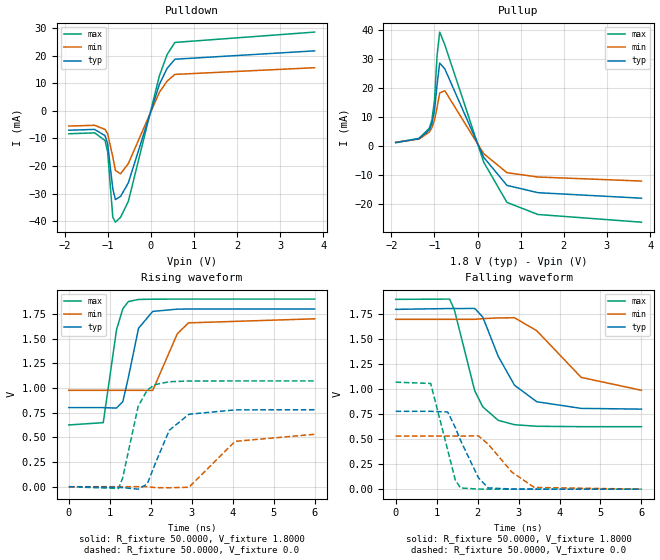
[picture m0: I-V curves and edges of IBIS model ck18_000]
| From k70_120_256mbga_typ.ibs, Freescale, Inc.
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|   Model ck18_000
[Model]  ck18_000
Model_type Output
Polarity   Non-Inverting
Enable   Active-High
Vmeas =  0.9000V
Cref =   5.0000pF
Rref =   50.0000
C_comp   2.8000pF   2.5000pF   3.3000pF
[Temperature Range]   25.0000   0.1250k   -40.0000
[Voltage Range]   1.8000V   1.7000V   1.9000V
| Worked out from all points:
|   slope of the pulldown table from 0 to 0.27 V, typ, clamps not added: 22.3 ohm
|   slope of the pullup table from 0 to 0.27 V, typ, clamps not added: 37.5 ohm
|   rising waveform, R_fixture 50.0000, V_fixture 1.8000: 20-80 % time 293ps typ, 373ps min, 246ps max; typ from 0.801 V to 1.8 V
|   rising waveform, R_fixture 50.0000, V_fixture 0.0: 20-80 % time 500ps typ, 674ps min, 357ps max; typ from 0 V to 0.779 V
|   falling waveform, R_fixture 50.0000, V_fixture 1.8000: 20-80 % time 733ps typ, 978ps min, 525ps max; typ from 1.8 V to 0.801 V
|   falling waveform, R_fixture 50.0000, V_fixture 0.0: 20-80 % time 514ps typ, 712ps min, 368ps max; typ from 0.779 V to 0 V
[Pulldown]
|Voltage   I(typ)   I(min)   I(max)
-1.9V     -7.037mA   -5.533mA   -8.324mA
-1.3V     -6.759mA   -5.258mA   -7.996mA
-1.06V    -9.034mA   -6.76mA    -10.79mA
-1V       -11.86mA   -8.287mA   -14.83mA
-880mV    -28.27mA   -16.73mA   -38.55mA
-820mV    -32.16mA   -21.61mA   -40.36mA
-700mV    -31.04mA   -22.85mA   -38.58mA
-520mV    -26.11mA   -19.13mA   -32.84mA
200mV     9.554mA    6.678mA    12.65mA
380mV     15.35mA    10.75mA    20.37mA
560mV     18.67mA    13.17mA    24.75mA
3.8V      21.7mA     15.6mA     28.5mA
[Pullup]
|Voltage   I(typ)   I(min)   I(max)
-1.9V     1mA        1.1mA      1.1mA
-1.36V    2.41mA     2.26mA     2.49mA
-1.12V    5.43mA     4.68mA     5.99mA
-1.06V    7.67mA     6.21mA     8.88mA
-1V       12.14mA    8.827mA    15.62mA
-940mV    21.04mA    13.25mA    31.11mA
-880mV    28.52mA    18.18mA    39.21mA
-760mV    26.48mA    18.95mA    34.8mA
140mV     -4.032mA   -2.771mA   -5.67mA
680mV     -13.73mA   -9.342mA   -19.61mA
1.4V      -16.26mA   -10.85mA   -23.79mA
3.8V      -18.16mA   -12.24mA   -26.45mA
[Ramp]
| variable   typ   min   max
dV/dt_r  0.4676/0.4997n   0.3185/0.6741n   0.6427/0.3572n
dV/dt_f  0.5993/0.7334n   0.4262/0.9781n   0.7648/0.5253n
R_load = 50.0000
[Rising Waveform]
R_fixture= 50.0000
V_fixture= 1.8000
V_fixture_min= 1.7000
V_fixture_max= 1.9000
|time   V(typ)   V(min)   V(max)
0s        800.8mV    975.9mV    625.4mV
840.4ps   800.7mV    975.9mV    648.5mV
1.164ns   796.5mV    975.9mV    1.588V
1.319ns   861.3mV    975.9mV    1.802V
1.455ns   1.109V     975.9mV    1.875V
1.702ns   1.604V     975.9mV    1.896V
2.048ns   1.775V     974.7mV    1.899V
2.65ns    1.798V     1.55V      1.9V
2.923ns   1.799V     1.659V     1.9V
6ns       1.8V       1.7V       1.9V
[Rising Waveform]
R_fixture= 50.0000
V_fixture= 0.0
|time   V(typ)   V(min)   V(max)
0s        4.934nV    519nV      1.31nV
1.213ns   -6.54mV    633.1nV    -18.08mV
1.314ns   -9.397mV   1.012uV    87.92mV
1.692ns   -24.91mV   -15.11uV   812.3mV
1.916ns   28.54mV    -59.27uV   980mV
2.105ns   229.5mV    -9.104mV   1.034V
2.451ns   570.6mV    -10.76mV   1.063V
2.932ns   733.5mV    -5.567mV   1.07V
4.059ns   778mV      459.1mV    1.071V
6ns       779.4mV    530.8mV    1.071V
[Falling Waveform]
R_fixture= 50.0000
V_fixture= 1.8000
V_fixture_min= 1.7000
V_fixture_max= 1.9000
|time   V(typ)   V(min)   V(max)
0s        1.8V       1.7V       1.9V
1.316ns   1.808V     1.7V       1.903V
1.431ns   1.808V     1.7V       1.798V
1.93ns    1.809V     1.7V       984.4mV
2.126ns   1.723V     1.707V     824.3mV
2.503ns   1.33V      1.714V     689mV
2.901ns   1.04V      1.716V     645.3mV
3.444ns   875.1mV    1.586V     629.7mV
4.528ns   808.7mV    1.119V     625.6mV
6ns       801.2mV    989.7mV    625.4mV
[Falling Waveform]
R_fixture= 50.0000
V_fixture= 0.0
|time   V(typ)   V(min)   V(max)
0s        779.4mV    531.6mV    1.071V
854.8ps   779.4mV    531.6mV    1.058V
1.27ns    772.6mV    531.6mV    391.5mV
1.454ns   617.8mV    531.6mV    93.44mV
1.583ns   488.1mV    531.6mV    11.85mV
2.02ns    113.8mV    533.4mV    1.026mV
2.258ns   12.74mV    450.7mV    429.1uV
2.839ns   1.089mV    170.1mV    59.66uV
3.384ns   257.5uV    17.03mV    14.02uV
6ns       1.796uV    45.2uV     178.8nV
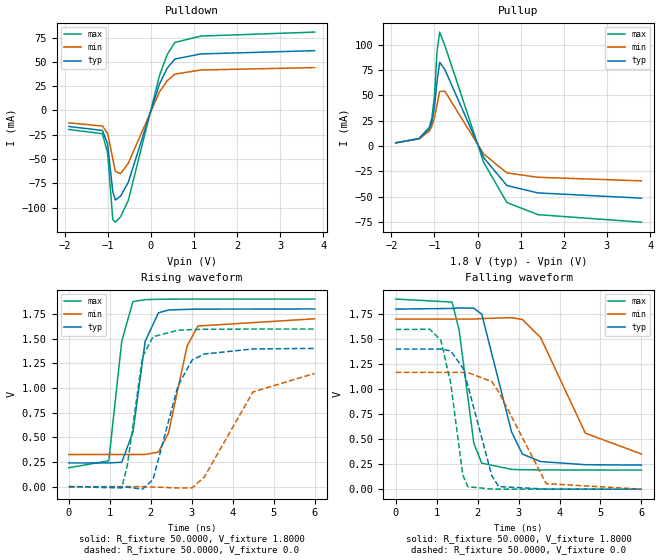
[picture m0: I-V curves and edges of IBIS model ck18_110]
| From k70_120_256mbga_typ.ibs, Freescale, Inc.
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|   Model ck18_110
[Model]  ck18_110
Model_type Output
Polarity   Non-Inverting
Enable   Active-High
Vmeas =  0.9000V
Cref =   5.0000pF
Rref =   50.0000
C_comp   2.8000pF   2.5000pF   3.3000pF
[Temperature Range]   25.0000   0.1250k   -40.0000
[Voltage Range]   1.8000V   1.7000V   1.9000V
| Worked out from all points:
|   slope of the pulldown table from 0 to 0.27 V, typ, clamps not added: 7.92 ohm
|   slope of the pullup table from 0 to 0.27 V, typ, clamps not added: 13.2 ohm
|   rising waveform, R_fixture 50.0000, V_fixture 1.8000: 20-80 % time 308ps typ, 421ps min, 248ps max; typ from 0.24 V to 1.8 V
|   rising waveform, R_fixture 50.0000, V_fixture 0.0: 20-80 % time 540ps typ, 918ps min, 314ps max; typ from 0 V to 1.4 V
|   falling waveform, R_fixture 50.0000, V_fixture 1.8000: 20-80 % time 520ps typ, 888ps min, 319ps max; typ from 1.8 V to 0.24 V
|   falling waveform, R_fixture 50.0000, V_fixture 0.0: 20-80 % time 552ps typ, 825ps min, 332ps max; typ from 1.4 V to 0 V
[Pulldown]
|Voltage   I(typ)   I(min)   I(max)
-1.9V     -16.47mA   -12.73mA   -19.56mA
-1.12V    -20.56mA   -16.02mA   -23.9mA
-1V       -34.44mA   -23.65mA   -43.79mA
-880mV    -83.64mA   -49.67mA   -112.2mA
-820mV    -92.06mA   -62.79mA   -114.9mA
-700mV    -88.12mA   -65.02mA   -109.4mA
-520mV    -73.78mA   -54.22mA   -92.51mA
200mV     26.91mA    18.89mA    35.48mA
380mV     43.37mA    30.47mA    57.34mA
560mV     52.89mA    37.37mA    69.96mA
1.16V     58.14mA    41.61mA    76.49mA
3.8V      61.5mA     44.1mA     80.6mA
[Pullup]
|Voltage   I(typ)   I(min)   I(max)
-1.9V     3mA        3.1mA      3.1mA
-1.36V    7.25mA     6.9mA      7.42mA
-1.12V    16.95mA    14.75mA    18.45mA
-1.06V    24.26mA    19.75mA    27.9mA
-1V       38.65mA    28.1mA     49.78mA
-940mV    64.52mA    41.14mA    94.22mA
-880mV    82.66mA    53.82mA    112.5mA
-760mV    75.53mA    54.14mA    99.26mA
140mV     -11.49mA   -7.896mA   -16.15mA
680mV     -39.15mA   -26.64mA   -55.9mA
1.4V      -46.38mA   -30.94mA   -67.85mA
3.8V      -51.55mA   -34.47mA   -75.3mA
[Ramp]
| variable   typ   min   max
dV/dt_r  0.8398/0.5395n   0.6881/0.9177n   0.9574/0.3141n
dV/dt_f  0.9357/0.5202n   0.8091/0.8879n   1.0253/0.3190n
R_load = 50.0000
[Rising Waveform]
R_fixture= 50.0000
V_fixture= 1.8000
V_fixture_min= 1.7000
V_fixture_max= 1.9000
|time   V(typ)   V(min)   V(max)
0s        240.2mV    325.7mV    191.2mV
975.8ps   240.2mV    325.7mV    261.9mV
1.292ns   247mV      325.7mV    1.472V
1.564ns   549.5mV    325.7mV    1.874V
1.864ns   1.472V     325.9mV    1.894V
2.189ns   1.761V     349.5mV    1.898V
2.432ns   1.789V     541.5mV    1.899V
2.888ns   1.796V     1.425V     1.9V
3.152ns   1.798V     1.627V     1.9V
6ns       1.8V       1.7V       1.9V
[Rising Waveform]
R_fixture= 50.0000
V_fixture= 0.0
|time   V(typ)   V(min)   V(max)
0s        2.256nV    247.9nV    586.3pV
1.293ns   -5.124mV   518nV      -13.56mV
1.43ns    -5.325mV   455.6nV    217.5mV
1.797ns   -25.49mV   87.12uV    1.312V
2.055ns   71.35mV    -3.419mV   1.519V
2.667ns   1.024V     -13.56mV   1.584V
3.012ns   1.284V     -12.49mV   1.591V
3.307ns   1.343V     96.68mV    1.594V
4.493ns   1.395V     959mV      1.596V
6ns       1.4V       1.147V     1.596V
[Falling Waveform]
R_fixture= 50.0000
V_fixture= 1.8000
V_fixture_min= 1.7000
V_fixture_max= 1.9000
|time   V(typ)   V(min)   V(max)
0s        1.8V       1.7V       1.9V
1.376ns   1.806V     1.7V       1.87V
1.547ns   1.811V     1.7V       1.592V
1.908ns   1.809V     1.7V       458.2mV
2.102ns   1.748V     1.705V     260mV
2.829ns   572mV      1.714V     198mV
3.093ns   350.9mV    1.696V     194.5mV
3.538ns   276mV      1.515V     192.2mV
4.631ns   244.4mV    559.2mV    191.3mV
6ns       240.5mV    351.4mV    191.2mV
[Falling Waveform]
R_fixture= 50.0000
V_fixture= 0.0
|time   V(typ)   V(min)   V(max)
0s        1.4V       1.167V     1.596V
835.8ps   1.4V       1.167V     1.598V
1.102ns   1.4V       1.167V     1.488V
1.342ns   1.382V     1.167V     1.063V
1.637ns   1.214V     1.167V     143.4mV
1.76ns    1.038V     1.166V     25.07mV
2.346ns   135.6mV    1.075V     1.007mV
2.514ns   26.21mV    973.4mV    643.1uV
3.674ns   502uV      55.27mV    26.31uV
6ns       4.981uV    238.1uV    7.875nV
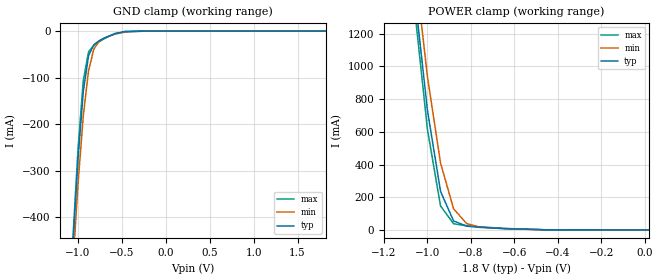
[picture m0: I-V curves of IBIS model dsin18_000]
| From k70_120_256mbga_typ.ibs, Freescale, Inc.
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|   Model dsin18_000
[Model]  dsin18_000
Model_type Input
Polarity   Non-Inverting
Enable   Active-High
Vinl =   0.6500V
Vinh =   1.1500V
C_comp   2.8000pF   2.5000pF   3.3000pF
[Temperature Range]   25.0000   0.1250k   -40.0000
[Voltage Range]   1.8000V   1.7000V   1.9000V
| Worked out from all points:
|   GND clamp passes 1 mA (typ) near -0.46 V on its own axis
|   POWER clamp passes 1 mA (typ) near -0.45 V on its own axis
[GND_clamp]
|Voltage   I(typ)   I(min)   I(max)
-1.9V     -3.878A    -3.837A    -3.924A
-1.06V    -463.9mA   -508.9mA   -451.7mA
-1V       -275.3mA   -328.7mA   -253.8mA
-940mV    -130mA     -182.2mA   -106.3mA
-880mV    -52.76mA   -84.89mA   -44.65mA
-820mV    -29.19mA   -38.6mA    -30.71mA
-760mV    -20.79mA   -21.86mA   -22.97mA
-700mV    -14.85mA   -14.77mA   -16.07mA
-580mV    -5.674mA   -6.612mA   -5.186mA
-460mV    -1.038mA   -1.902mA   -615.1uA
-220mV    -1.001uA   -15.63uA   -61.01nA
1.82V     927pA      961.6nA    217.2pA
[POWER_clamp]
|Voltage   I(typ)   I(min)   I(max)
-1.9V     14.99A     14.89A     15.1A
-1.06V    1.452A     1.634A     1.361A
-1V       729.6mA    935mA      612.3mA
-940mV    235.7mA    409.7mA    146.8mA
-880mV    55.12mA    129.3mA    38.22mA
-820mV    23.43mA    39.21mA    25.26mA
-760mV    15.93mA    17.42mA    19.04mA
-640mV    7.842mA    7.36mA     9.207mA
-460mV    1.151mA    1.601mA    977.3uA
20mV      403.6pA    26.53nA    232.4pA
